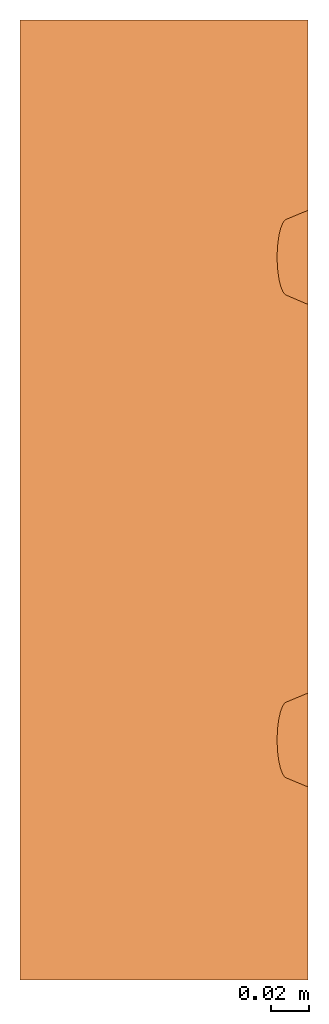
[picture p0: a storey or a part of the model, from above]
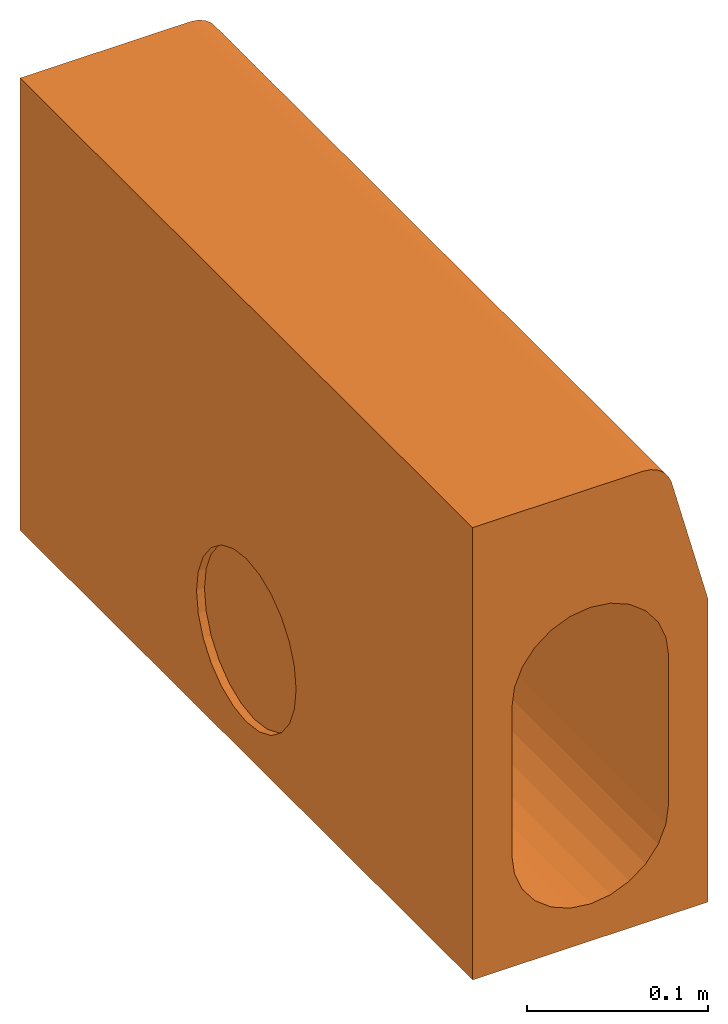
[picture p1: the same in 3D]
Properties of the parts of a building model (IFC2X3)

# File
Description: ViewDefinition [CoordinationView]
File name: 7961 - KDHB305 Channel - 500mm LG.ifc
Time: 2013-09-12T12:40:56
Written by: Autodesk Revit 2013
Made in: 20120221_2030(x64)

# IfcProject, Project Number
LongName: Project Name; Phase: Project Status

# IfcSite, Default
RefLatitude: 42, 21, 30, 344238; RefLongitude: -71, -3, -35, -194702; RefElevation: 0 mm

# IfcBuilding
Pset_BuildingCommon - NumberOfStoreys: 2
Other - Client Name: Owner; Project Status: Project Status; Project Issue Date: Issue Date; Project Name: Project Name; Project Address: Enter address here; Project Number: Project Number

# IfcBuildingStorey (2)
Constraints - Elevation Base: 0
Graphics - Symbol at End 2 Default: yes; Symbol at End 1 Default: no; Symbol: M_Level Head - Circle: M_Level Head - Circle; Color: 0; Line Weight: 1; Line Pattern: Center
Identity Data - Structural: no; Building Story: yes
Dimensions - Computation Height: 0 mm
Name | LongName = Name | Elevation (mm) = Constraints, Elevation (mm)
T.O. Fnd. Wall | T.O. Fnd. Wall | -300
Level 1 | Level 1 | 0

# IfcBuildingElementProxy: 7961 - KDHB305 Channel - 500mm LG, Civil-Drainage-Channel-ACO-KerbDrain-HB305 - PART 1:7961 - KDHB305 Channel - 500mm LG:7961 - KDHB305 Channel - 500mm LG:255899
In: T.O. Fnd. Wall
Material: ACO Polymer Concrete.
Dimensions - Void_Width: 150 mm; I/O Endcap Void depth: 6000 mm; Staright Void Depth: -180 mm; Void_Length: 500 mm; Volume: 12865060 mm3
Green Building Properties - End Cap Recyclable: N/A; Channel Recycled Material Content: 20% minimum; End Cap Recycled Material Content: N/A; Access Cover/Frame Recyclable: N/A; Access Cover/Frame Recycled Material Content: N/A; Channel Recyclable: Fully recyclable
Other - Revision: 1; CreatedBy: www.aco.co.uk
Constraints - Moves With Nearby Elements: no; Level: Level: Level 1
Phasing - Phase Created: Phase 1
Pset_BuildingElementProxyCommon - Reference: 7961 - KDHB305 Channel - 500mm LG
Identity Data - Model: ACO KerbDrain HB305; Model Description: Combined kerb and drainage system; Manufacturer: ACO Technologies plc - ACO Water Management Division; Installation guidelines: http://www.aco.co.uk/download.php?id=120 http://www.aco.co.uk/download.php?id=120; Assembly Description: Rain Water Drainage; Type Comments: ACO KerbDrain HB305 half battered kerb unit 500mm long; Address: ACO Business Park, Hitchin Road, Shefford, Bedfordshire, United Kingdom SG17 5TE; Product Page URL: http://www.aco.co.uk/product_detail.php?id=3; E-mail Technical: technical@aco.co.uk; Cost: 0; Telephone: +44 (0)1462 816666; OmniClass Title: Rainwater Removal; Maintenance guidelines: http://www.aco.co.uk/download.php?id=120; Fax: +44 (0)1462 815895; Product brochure: http://www.aco.co.uk/download.php?id=120; URL: www.aco.co.uk; Product Code: 7961; Assembly Code: D2040; OmniClass Number: 23.70.50.24; Price: POA - contact ACO; E-mail Sales: customersupport@aco.co.uk
Data - Invert Depth: 280mm; Drainage Slot Intake area: 14592mm²/m; Product Weight: 26.2 kg; Concrete Surround Volume - Load Class A 15 - D 400 - Concrete Pavement: 0.14m³/m; Load Class: A 15 - D 400; Connection Pipe O.D: N/A; Hydraulic Performance: http://www.aco.co.uk/download.php?id=120; Channel C.S.A: 0.02m²; Concrete Surround Volume - Load Class A 15 - D 400 - Grass or Asphalt Pavement: 0.13m³/m; Product Dimensions: 500mm x 150mm x 305mm (LxWxH); ACO Hydraulic Design Software: http://www.acodesign.co.uk; Installation - Concrete Grade: Refer to brochure; Product Standard: BS EN 1433:2002, CE marked, Kitemarked; Drainage Slot Width: 50mm
Construction - I/O Pipe: no; KDHB305 - LH drop kerb: no; KDHB305 - Channel unit - 500mm: yes; KDHB305 - RH drop kerb: no; KDHB305 - Flush RH dropkerb: no; KDHB305 - Centre stone: no; KDHB305 - Flush LH dropkerb: no; KDHB305 - Closing end cap: no; KDHB305 - Perforated centre stone: no; KDHB305 - RH Inlet/outlet end cap: no; KDHB305 - Blind unit: no; KDHB305 - Drainable centre stone: no; KDHB305 - Channel unit - 1000mm: no; KDHB305 - Channel unit - 250mm: no; KDHB305 - LH Inlet/Outlet end cap: no; KDHB305 - Access Unit: no
General - SerialNumber: 0.000000; TagNumber: 0.000000
Materials and Finishes - Access Cover/Frame Colour: N/A; Channel Material: Vienite® Synthetic Resin Concrete; Connection Pipe Material Colour: N/A; Connection Pipe Material: N/A; Access Cover/Frame Material: N/A; Access Cover/Frame Finish: N/A; End Cap Colour: N/A; Channel Colour: Grey; End Cap Material: N/A

# IfcOpeningElement: Recess (2)
In: Level 1
Phasing - Phase Created: Phase 1
Structural - Enable Analytical Model: no; Structural: no
Dimensions - Volume: 21192932206 mm3; Area: 53016081 mm2; Perimeter: 29157.2 mm; Thickness: 400 mm
Constraints - Height Offset From Level: 0 mm; Room Bounding: yes; Level: Level: Level 1; Related to Mass: no
Analytical Properties - Roughness: 1; Absorptance: 0.1
Graphics - Coarse Scale Fill Color: 0
Construction - Default Thickness: 400 mm; Function: 0

# IfcSlab: Floor:Generic Floor - 400mm, Floor:Generic Floor - 400mm:184025
In: Level 1
PredefinedType: FLOOR; Material: Default Floor 400 mm
Phasing - Phase Created: Phase 1
Structural - Enable Analytical Model: no; Structural: no
Dimensions - Volume: 21192932206 mm3; Area: 53016081 mm2; Perimeter: 29157.2 mm; Thickness: 400 mm
Constraints - Height Offset From Level: 0 mm; Room Bounding: yes; Level: Level: Level 1; Related to Mass: no
Pset_SlabCommon - Reference: Generic Floor - 400mm; IsExternal: no; LoadBearing: yes
Analytical Properties - Roughness: 1; Absorptance: 0.1
Graphics - Coarse Scale Fill Color: 0
Construction - Default Thickness: 400 mm; Function: 0
